VERSION 5.7 ;
  NOWIREEXTENSIONATPIN ON ;
  DIVIDERCHAR "/" ;
  BUSBITCHARS "[]" ;
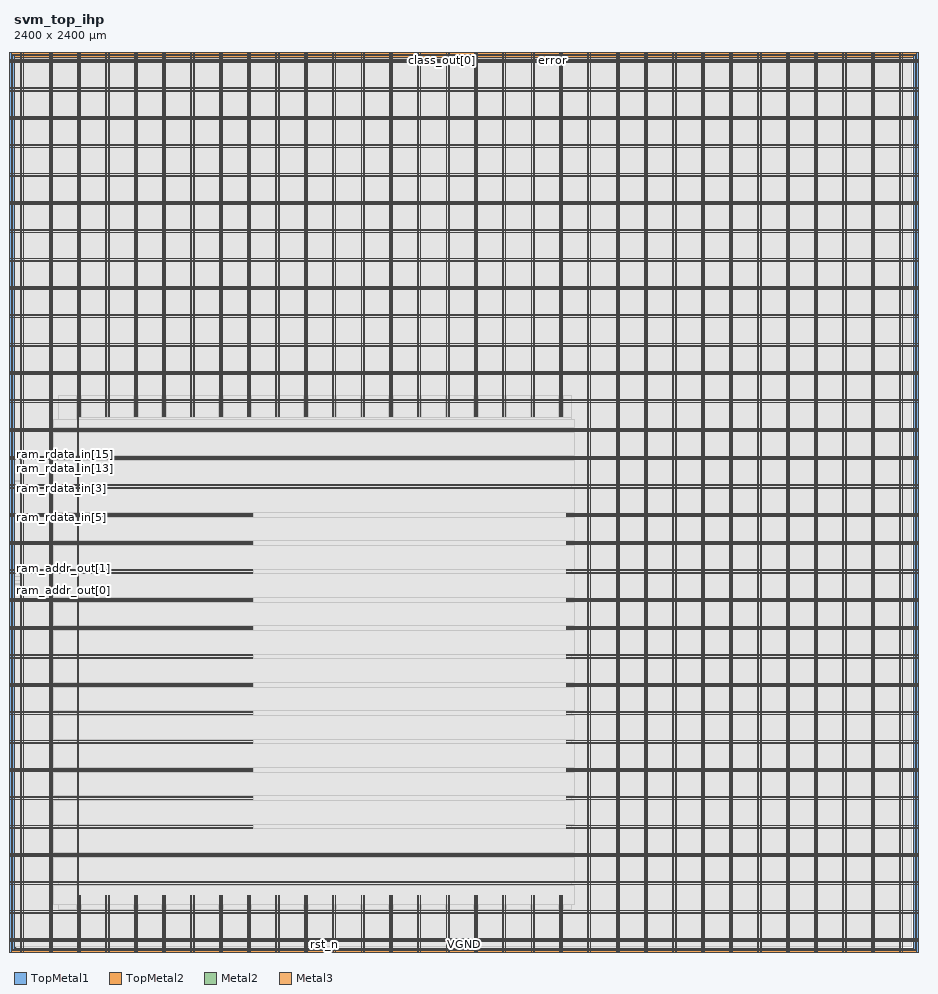
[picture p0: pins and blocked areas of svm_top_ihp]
MACRO svm_top_ihp
  CLASS BLOCK ;
  FOREIGN svm_top_ihp ;
  ORIGIN 0.000 0.000 ;
  SIZE 2400.000 BY 2400.000 ;
  PIN VGND
    DIRECTION INOUT ;
    USE GROUND ;
    PORT
      LAYER TopMetal1 ;
        RECT -10.740 -1.380 -5.740 2397.900 ;
    END
    PORT
      LAYER TopMetal1 ;
        RECT 2405.740 -1.380 2410.740 2397.900 ;
    END
    PORT
      LAYER TopMetal2 ;
        RECT -10.740 -1.380 2410.740 3.620 ;
    END
    PORT
      LAYER TopMetal2 ;
        RECT -10.740 2392.900 2410.740 2397.900 ;
    END
    PORT
      LAYER TopMetal1 ;
        RECT 24.460 -1.380 26.660 2397.900 ;
    END
    PORT
      LAYER TopMetal1 ;
        RECT 100.060 -1.380 102.260 2397.900 ;
    END
    PORT
      LAYER TopMetal1 ;
        RECT 175.660 -1.380 177.860 150.920 ;
    END
    PORT
      LAYER TopMetal1 ;
        RECT 175.660 1427.940 177.860 2397.900 ;
    END
    PORT
      LAYER TopMetal1 ;
        RECT 251.260 -1.380 253.460 150.920 ;
    END
    PORT
      LAYER TopMetal1 ;
        RECT 251.260 1427.940 253.460 2397.900 ;
    END
    PORT
      LAYER TopMetal1 ;
        RECT 326.860 -1.380 329.060 150.920 ;
    END
    PORT
      LAYER TopMetal1 ;
        RECT 326.860 1427.940 329.060 2397.900 ;
    END
    PORT
      LAYER TopMetal1 ;
        RECT 402.460 -1.380 404.660 150.920 ;
    END
    PORT
      LAYER TopMetal1 ;
        RECT 402.460 1427.940 404.660 2397.900 ;
    END
    PORT
      LAYER TopMetal1 ;
        RECT 478.060 -1.380 480.260 150.920 ;
    END
    PORT
      LAYER TopMetal1 ;
        RECT 478.060 1427.940 480.260 2397.900 ;
    END
    PORT
      LAYER TopMetal1 ;
        RECT 553.660 -1.380 555.860 150.920 ;
    END
    PORT
      LAYER TopMetal1 ;
        RECT 553.660 1427.940 555.860 2397.900 ;
    END
    PORT
      LAYER TopMetal1 ;
        RECT 629.260 -1.380 631.460 150.920 ;
    END
    PORT
      LAYER TopMetal1 ;
        RECT 629.260 1427.940 631.460 2397.900 ;
    END
    PORT
      LAYER TopMetal1 ;
        RECT 704.860 -1.380 707.060 150.920 ;
    END
    PORT
      LAYER TopMetal1 ;
        RECT 704.860 1427.940 707.060 2397.900 ;
    END
    PORT
      LAYER TopMetal1 ;
        RECT 780.460 -1.380 782.660 150.920 ;
    END
    PORT
      LAYER TopMetal1 ;
        RECT 780.460 1427.940 782.660 2397.900 ;
    END
    PORT
      LAYER TopMetal1 ;
        RECT 856.060 -1.380 858.260 150.920 ;
    END
    PORT
      LAYER TopMetal1 ;
        RECT 856.060 1427.940 858.260 2397.900 ;
    END
    PORT
      LAYER TopMetal1 ;
        RECT 931.660 -1.380 933.860 150.920 ;
    END
    PORT
      LAYER TopMetal1 ;
        RECT 931.660 1427.940 933.860 2397.900 ;
    END
    PORT
      LAYER TopMetal1 ;
        RECT 1007.260 -1.380 1009.460 150.920 ;
    END
    PORT
      LAYER TopMetal1 ;
        RECT 1007.260 1427.940 1009.460 2397.900 ;
    END
    PORT
      LAYER TopMetal1 ;
        RECT 1082.860 -1.380 1085.060 150.920 ;
    END
    PORT
      LAYER TopMetal1 ;
        RECT 1082.860 1427.940 1085.060 2397.900 ;
    END
    PORT
      LAYER TopMetal1 ;
        RECT 1158.460 -1.380 1160.660 150.920 ;
    END
    PORT
      LAYER TopMetal1 ;
        RECT 1158.460 1427.940 1160.660 2397.900 ;
    END
    PORT
      LAYER TopMetal1 ;
        RECT 1234.060 -1.380 1236.260 150.920 ;
    END
    PORT
      LAYER TopMetal1 ;
        RECT 1234.060 1427.940 1236.260 2397.900 ;
    END
    PORT
      LAYER TopMetal1 ;
        RECT 1309.660 -1.380 1311.860 150.920 ;
    END
    PORT
      LAYER TopMetal1 ;
        RECT 1309.660 1427.940 1311.860 2397.900 ;
    END
    PORT
      LAYER TopMetal1 ;
        RECT 1385.260 -1.380 1387.460 150.920 ;
    END
    PORT
      LAYER TopMetal1 ;
        RECT 1385.260 1427.940 1387.460 2397.900 ;
    END
    PORT
      LAYER TopMetal1 ;
        RECT 1460.860 -1.380 1463.060 150.920 ;
    END
    PORT
      LAYER TopMetal1 ;
        RECT 1460.860 1427.940 1463.060 2397.900 ;
    END
    PORT
      LAYER TopMetal1 ;
        RECT 1536.460 -1.380 1538.660 2397.900 ;
    END
    PORT
      LAYER TopMetal1 ;
        RECT 1612.060 -1.380 1614.260 2397.900 ;
    END
    PORT
      LAYER TopMetal1 ;
        RECT 1687.660 -1.380 1689.860 2397.900 ;
    END
    PORT
      LAYER TopMetal1 ;
        RECT 1763.260 -1.380 1765.460 2397.900 ;
    END
    PORT
      LAYER TopMetal1 ;
        RECT 1838.860 -1.380 1841.060 2397.900 ;
    END
    PORT
      LAYER TopMetal1 ;
        RECT 1914.460 -1.380 1916.660 2397.900 ;
    END
    PORT
      LAYER TopMetal1 ;
        RECT 1990.060 -1.380 1992.260 2397.900 ;
    END
    PORT
      LAYER TopMetal1 ;
        RECT 2065.660 -1.380 2067.860 2397.900 ;
    END
    PORT
      LAYER TopMetal1 ;
        RECT 2141.260 -1.380 2143.460 2397.900 ;
    END
    PORT
      LAYER TopMetal1 ;
        RECT 2216.860 -1.380 2219.060 2397.900 ;
    END
    PORT
      LAYER TopMetal1 ;
        RECT 2292.460 -1.380 2294.660 2397.900 ;
    END
    PORT
      LAYER TopMetal1 ;
        RECT 2368.060 -1.380 2370.260 2397.900 ;
    END
    PORT
      LAYER TopMetal2 ;
        RECT -10.740 33.820 2410.740 36.020 ;
    END
    PORT
      LAYER TopMetal2 ;
        RECT -10.740 109.420 2410.740 111.620 ;
    END
    PORT
      LAYER TopMetal2 ;
        RECT -10.740 185.020 2410.740 187.220 ;
    END
    PORT
      LAYER TopMetal2 ;
        RECT -10.740 260.620 2410.740 262.820 ;
    END
    PORT
      LAYER TopMetal2 ;
        RECT -10.740 336.220 637.000 338.420 ;
    END
    PORT
      LAYER TopMetal2 ;
        RECT -10.740 411.820 637.000 414.020 ;
    END
    PORT
      LAYER TopMetal2 ;
        RECT -10.740 487.420 637.000 489.620 ;
    END
    PORT
      LAYER TopMetal2 ;
        RECT -10.740 563.020 637.000 565.220 ;
    END
    PORT
      LAYER TopMetal2 ;
        RECT -10.740 638.620 637.000 640.820 ;
    END
    PORT
      LAYER TopMetal2 ;
        RECT -10.740 714.220 637.000 716.420 ;
    END
    PORT
      LAYER TopMetal2 ;
        RECT -10.740 789.820 637.000 792.020 ;
    END
    PORT
      LAYER TopMetal2 ;
        RECT -10.740 865.420 637.000 867.620 ;
    END
    PORT
      LAYER TopMetal2 ;
        RECT -10.740 941.020 637.000 943.220 ;
    END
    PORT
      LAYER TopMetal2 ;
        RECT -10.740 1016.620 637.000 1018.820 ;
    END
    PORT
      LAYER TopMetal2 ;
        RECT -10.740 1092.220 637.000 1094.420 ;
    END
    PORT
      LAYER TopMetal2 ;
        RECT -10.740 1167.820 637.000 1170.020 ;
    END
    PORT
      LAYER TopMetal2 ;
        RECT -10.740 1243.420 2410.740 1245.620 ;
    END
    PORT
      LAYER TopMetal2 ;
        RECT -10.740 1319.020 2410.740 1321.220 ;
    END
    PORT
      LAYER TopMetal2 ;
        RECT -10.740 1394.620 2410.740 1396.820 ;
    END
    PORT
      LAYER TopMetal2 ;
        RECT -10.740 1470.220 2410.740 1472.420 ;
    END
    PORT
      LAYER TopMetal2 ;
        RECT -10.740 1545.820 2410.740 1548.020 ;
    END
    PORT
      LAYER TopMetal2 ;
        RECT -10.740 1621.420 2410.740 1623.620 ;
    END
    PORT
      LAYER TopMetal2 ;
        RECT -10.740 1697.020 2410.740 1699.220 ;
    END
    PORT
      LAYER TopMetal2 ;
        RECT -10.740 1772.620 2410.740 1774.820 ;
    END
    PORT
      LAYER TopMetal2 ;
        RECT -10.740 1848.220 2410.740 1850.420 ;
    END
    PORT
      LAYER TopMetal2 ;
        RECT -10.740 1923.820 2410.740 1926.020 ;
    END
    PORT
      LAYER TopMetal2 ;
        RECT -10.740 1999.420 2410.740 2001.620 ;
    END
    PORT
      LAYER TopMetal2 ;
        RECT -10.740 2075.020 2410.740 2077.220 ;
    END
    PORT
      LAYER TopMetal2 ;
        RECT -10.740 2150.620 2410.740 2152.820 ;
    END
    PORT
      LAYER TopMetal2 ;
        RECT -10.740 2226.220 2410.740 2228.420 ;
    END
    PORT
      LAYER TopMetal2 ;
        RECT -10.740 2301.820 2410.740 2304.020 ;
    END
    PORT
      LAYER TopMetal2 ;
        RECT -10.740 2377.420 2410.740 2379.620 ;
    END
    PORT
      LAYER TopMetal2 ;
        RECT 1474.640 336.220 2410.740 338.420 ;
    END
    PORT
      LAYER TopMetal2 ;
        RECT 1474.640 411.820 2410.740 414.020 ;
    END
    PORT
      LAYER TopMetal2 ;
        RECT 1474.640 487.420 2410.740 489.620 ;
    END
    PORT
      LAYER TopMetal2 ;
        RECT 1474.640 563.020 2410.740 565.220 ;
    END
    PORT
      LAYER TopMetal2 ;
        RECT 1474.640 638.620 2410.740 640.820 ;
    END
    PORT
      LAYER TopMetal2 ;
        RECT 1474.640 714.220 2410.740 716.420 ;
    END
    PORT
      LAYER TopMetal2 ;
        RECT 1474.640 789.820 2410.740 792.020 ;
    END
    PORT
      LAYER TopMetal2 ;
        RECT 1474.640 865.420 2410.740 867.620 ;
    END
    PORT
      LAYER TopMetal2 ;
        RECT 1474.640 941.020 2410.740 943.220 ;
    END
    PORT
      LAYER TopMetal2 ;
        RECT 1474.640 1016.620 2410.740 1018.820 ;
    END
    PORT
      LAYER TopMetal2 ;
        RECT 1474.640 1092.220 2410.740 1094.420 ;
    END
    PORT
      LAYER TopMetal2 ;
        RECT 1474.640 1167.820 2410.740 1170.020 ;
    END
  END VGND
  PIN VPWR
    DIRECTION INOUT ;
    USE POWER ;
    PORT
      LAYER TopMetal1 ;
        RECT -3.740 5.620 1.260 2390.900 ;
    END
    PORT
      LAYER TopMetal1 ;
        RECT 2398.740 5.620 2403.740 2390.900 ;
    END
    PORT
      LAYER TopMetal2 ;
        RECT -3.740 5.620 2403.740 10.620 ;
    END
    PORT
      LAYER TopMetal2 ;
        RECT -3.740 2385.900 2403.740 2390.900 ;
    END
    PORT
      LAYER TopMetal1 ;
        RECT 18.260 -1.380 20.460 2397.900 ;
    END
    PORT
      LAYER TopMetal1 ;
        RECT 93.860 -1.380 96.060 2397.900 ;
    END
    PORT
      LAYER TopMetal1 ;
        RECT 169.460 -1.380 171.660 2397.900 ;
    END
    PORT
      LAYER TopMetal1 ;
        RECT 245.060 -1.380 247.260 150.920 ;
    END
    PORT
      LAYER TopMetal1 ;
        RECT 245.060 1427.940 247.260 2397.900 ;
    END
    PORT
      LAYER TopMetal1 ;
        RECT 320.660 -1.380 322.860 150.920 ;
    END
    PORT
      LAYER TopMetal1 ;
        RECT 320.660 1427.940 322.860 2397.900 ;
    END
    PORT
      LAYER TopMetal1 ;
        RECT 396.260 -1.380 398.460 150.920 ;
    END
    PORT
      LAYER TopMetal1 ;
        RECT 396.260 1427.940 398.460 2397.900 ;
    END
    PORT
      LAYER TopMetal1 ;
        RECT 471.860 -1.380 474.060 150.920 ;
    END
    PORT
      LAYER TopMetal1 ;
        RECT 471.860 1427.940 474.060 2397.900 ;
    END
    PORT
      LAYER TopMetal1 ;
        RECT 547.460 -1.380 549.660 150.920 ;
    END
    PORT
      LAYER TopMetal1 ;
        RECT 547.460 1427.940 549.660 2397.900 ;
    END
    PORT
      LAYER TopMetal1 ;
        RECT 623.060 -1.380 625.260 150.920 ;
    END
    PORT
      LAYER TopMetal1 ;
        RECT 623.060 1427.940 625.260 2397.900 ;
    END
    PORT
      LAYER TopMetal1 ;
        RECT 698.660 -1.380 700.860 150.920 ;
    END
    PORT
      LAYER TopMetal1 ;
        RECT 698.660 1427.940 700.860 2397.900 ;
    END
    PORT
      LAYER TopMetal1 ;
        RECT 774.260 -1.380 776.460 150.920 ;
    END
    PORT
      LAYER TopMetal1 ;
        RECT 774.260 1427.940 776.460 2397.900 ;
    END
    PORT
      LAYER TopMetal1 ;
        RECT 849.860 -1.380 852.060 150.920 ;
    END
    PORT
      LAYER TopMetal1 ;
        RECT 849.860 1427.940 852.060 2397.900 ;
    END
    PORT
      LAYER TopMetal1 ;
        RECT 925.460 -1.380 927.660 150.920 ;
    END
    PORT
      LAYER TopMetal1 ;
        RECT 925.460 1427.940 927.660 2397.900 ;
    END
    PORT
      LAYER TopMetal1 ;
        RECT 1001.060 -1.380 1003.260 150.920 ;
    END
    PORT
      LAYER TopMetal1 ;
        RECT 1001.060 1427.940 1003.260 2397.900 ;
    END
    PORT
      LAYER TopMetal1 ;
        RECT 1076.660 -1.380 1078.860 150.920 ;
    END
    PORT
      LAYER TopMetal1 ;
        RECT 1076.660 1427.940 1078.860 2397.900 ;
    END
    PORT
      LAYER TopMetal1 ;
        RECT 1152.260 -1.380 1154.460 150.920 ;
    END
    PORT
      LAYER TopMetal1 ;
        RECT 1152.260 1427.940 1154.460 2397.900 ;
    END
    PORT
      LAYER TopMetal1 ;
        RECT 1227.860 -1.380 1230.060 150.920 ;
    END
    PORT
      LAYER TopMetal1 ;
        RECT 1227.860 1427.940 1230.060 2397.900 ;
    END
    PORT
      LAYER TopMetal1 ;
        RECT 1303.460 -1.380 1305.660 150.920 ;
    END
    PORT
      LAYER TopMetal1 ;
        RECT 1303.460 1427.940 1305.660 2397.900 ;
    END
    PORT
      LAYER TopMetal1 ;
        RECT 1379.060 -1.380 1381.260 150.920 ;
    END
    PORT
      LAYER TopMetal1 ;
        RECT 1379.060 1427.940 1381.260 2397.900 ;
    END
    PORT
      LAYER TopMetal1 ;
        RECT 1454.660 -1.380 1456.860 150.920 ;
    END
    PORT
      LAYER TopMetal1 ;
        RECT 1454.660 1427.940 1456.860 2397.900 ;
    END
    PORT
      LAYER TopMetal1 ;
        RECT 1530.260 -1.380 1532.460 2397.900 ;
    END
    PORT
      LAYER TopMetal1 ;
        RECT 1605.860 -1.380 1608.060 2397.900 ;
    END
    PORT
      LAYER TopMetal1 ;
        RECT 1681.460 -1.380 1683.660 2397.900 ;
    END
    PORT
      LAYER TopMetal1 ;
        RECT 1757.060 -1.380 1759.260 2397.900 ;
    END
    PORT
      LAYER TopMetal1 ;
        RECT 1832.660 -1.380 1834.860 2397.900 ;
    END
    PORT
      LAYER TopMetal1 ;
        RECT 1908.260 -1.380 1910.460 2397.900 ;
    END
    PORT
      LAYER TopMetal1 ;
        RECT 1983.860 -1.380 1986.060 2397.900 ;
    END
    PORT
      LAYER TopMetal1 ;
        RECT 2059.460 -1.380 2061.660 2397.900 ;
    END
    PORT
      LAYER TopMetal1 ;
        RECT 2135.060 -1.380 2137.260 2397.900 ;
    END
    PORT
      LAYER TopMetal1 ;
        RECT 2210.660 -1.380 2212.860 2397.900 ;
    END
    PORT
      LAYER TopMetal1 ;
        RECT 2286.260 -1.380 2288.460 2397.900 ;
    END
    PORT
      LAYER TopMetal1 ;
        RECT 2361.860 -1.380 2364.060 2397.900 ;
    END
    PORT
      LAYER TopMetal2 ;
        RECT -10.740 27.620 2410.740 29.820 ;
    END
    PORT
      LAYER TopMetal2 ;
        RECT -10.740 103.220 2410.740 105.420 ;
    END
    PORT
      LAYER TopMetal2 ;
        RECT -10.740 178.820 2410.740 181.020 ;
    END
    PORT
      LAYER TopMetal2 ;
        RECT -10.740 254.420 2410.740 256.620 ;
    END
    PORT
      LAYER TopMetal2 ;
        RECT -10.740 330.020 637.000 332.220 ;
    END
    PORT
      LAYER TopMetal2 ;
        RECT -10.740 405.620 637.000 407.820 ;
    END
    PORT
      LAYER TopMetal2 ;
        RECT -10.740 481.220 637.000 483.420 ;
    END
    PORT
      LAYER TopMetal2 ;
        RECT -10.740 556.820 637.000 559.020 ;
    END
    PORT
      LAYER TopMetal2 ;
        RECT -10.740 632.420 637.000 634.620 ;
    END
    PORT
      LAYER TopMetal2 ;
        RECT -10.740 708.020 637.000 710.220 ;
    END
    PORT
      LAYER TopMetal2 ;
        RECT -10.740 783.620 637.000 785.820 ;
    END
    PORT
      LAYER TopMetal2 ;
        RECT -10.740 859.220 637.000 861.420 ;
    END
    PORT
      LAYER TopMetal2 ;
        RECT -10.740 934.820 637.000 937.020 ;
    END
    PORT
      LAYER TopMetal2 ;
        RECT -10.740 1010.420 637.000 1012.620 ;
    END
    PORT
      LAYER TopMetal2 ;
        RECT -10.740 1086.020 637.000 1088.220 ;
    END
    PORT
      LAYER TopMetal2 ;
        RECT -10.740 1161.620 637.000 1163.820 ;
    END
    PORT
      LAYER TopMetal2 ;
        RECT -10.740 1237.220 2410.740 1239.420 ;
    END
    PORT
      LAYER TopMetal2 ;
        RECT -10.740 1312.820 2410.740 1315.020 ;
    END
    PORT
      LAYER TopMetal2 ;
        RECT -10.740 1388.420 2410.740 1390.620 ;
    END
    PORT
      LAYER TopMetal2 ;
        RECT -10.740 1464.020 2410.740 1466.220 ;
    END
    PORT
      LAYER TopMetal2 ;
        RECT -10.740 1539.620 2410.740 1541.820 ;
    END
    PORT
      LAYER TopMetal2 ;
        RECT -10.740 1615.220 2410.740 1617.420 ;
    END
    PORT
      LAYER TopMetal2 ;
        RECT -10.740 1690.820 2410.740 1693.020 ;
    END
    PORT
      LAYER TopMetal2 ;
        RECT -10.740 1766.420 2410.740 1768.620 ;
    END
    PORT
      LAYER TopMetal2 ;
        RECT -10.740 1842.020 2410.740 1844.220 ;
    END
    PORT
      LAYER TopMetal2 ;
        RECT -10.740 1917.620 2410.740 1919.820 ;
    END
    PORT
      LAYER TopMetal2 ;
        RECT -10.740 1993.220 2410.740 1995.420 ;
    END
    PORT
      LAYER TopMetal2 ;
        RECT -10.740 2068.820 2410.740 2071.020 ;
    END
    PORT
      LAYER TopMetal2 ;
        RECT -10.740 2144.420 2410.740 2146.620 ;
    END
    PORT
      LAYER TopMetal2 ;
        RECT -10.740 2220.020 2410.740 2222.220 ;
    END
    PORT
      LAYER TopMetal2 ;
        RECT -10.740 2295.620 2410.740 2297.820 ;
    END
    PORT
      LAYER TopMetal2 ;
        RECT -10.740 2371.220 2410.740 2373.420 ;
    END
    PORT
      LAYER TopMetal2 ;
        RECT 1474.640 330.020 2410.740 332.220 ;
    END
    PORT
      LAYER TopMetal2 ;
        RECT 1474.640 405.620 2410.740 407.820 ;
    END
    PORT
      LAYER TopMetal2 ;
        RECT 1474.640 481.220 2410.740 483.420 ;
    END
    PORT
      LAYER TopMetal2 ;
        RECT 1474.640 556.820 2410.740 559.020 ;
    END
    PORT
      LAYER TopMetal2 ;
        RECT 1474.640 632.420 2410.740 634.620 ;
    END
    PORT
      LAYER TopMetal2 ;
        RECT 1474.640 708.020 2410.740 710.220 ;
    END
    PORT
      LAYER TopMetal2 ;
        RECT 1474.640 783.620 2410.740 785.820 ;
    END
    PORT
      LAYER TopMetal2 ;
        RECT 1474.640 859.220 2410.740 861.420 ;
    END
    PORT
      LAYER TopMetal2 ;
        RECT 1474.640 934.820 2410.740 937.020 ;
    END
    PORT
      LAYER TopMetal2 ;
        RECT 1474.640 1010.420 2410.740 1012.620 ;
    END
    PORT
      LAYER TopMetal2 ;
        RECT 1474.640 1086.020 2410.740 1088.220 ;
    END
    PORT
      LAYER TopMetal2 ;
        RECT 1474.640 1161.620 2410.740 1163.820 ;
    END
  END VPWR
  PIN class_out[0]
    DIRECTION OUTPUT ;
    USE SIGNAL ;
    ANTENNADIFFAREA 0.708600 ;
    PORT
      LAYER Metal2 ;
        RECT 1141.720 2399.600 1142.120 2400.000 ;
    END
  END class_out[0]
  PIN class_out[1]
    DIRECTION OUTPUT ;
    USE SIGNAL ;
    ANTENNADIFFAREA 0.708600 ;
    PORT
      LAYER Metal2 ;
        RECT 1140.760 2399.600 1141.160 2400.000 ;
    END
  END class_out[1]
  PIN class_out[2]
    DIRECTION OUTPUT ;
    USE SIGNAL ;
    ANTENNADIFFAREA 0.708600 ;
    PORT
      LAYER Metal2 ;
        RECT 1139.800 2399.600 1140.200 2400.000 ;
    END
  END class_out[2]
  PIN clk
    DIRECTION INPUT ;
    USE SIGNAL ;
    ANTENNAGATEAREA 2.901600 ;
    PORT
      LAYER Metal2 ;
        RECT 1374.040 2399.600 1374.440 2400.000 ;
    END
  END clk
  PIN done
    DIRECTION OUTPUT ;
    USE SIGNAL ;
    ANTENNADIFFAREA 0.708600 ;
    PORT
      LAYER Metal2 ;
        RECT 1183.000 2399.600 1183.400 2400.000 ;
    END
  END done
  PIN error
    DIRECTION OUTPUT ;
    USE SIGNAL ;
    ANTENNADIFFAREA 0.708600 ;
    PORT
      LAYER Metal2 ;
        RECT 1437.400 2399.600 1437.800 2400.000 ;
    END
  END error
  PIN error_code[0]
    DIRECTION OUTPUT ;
    USE SIGNAL ;
    ANTENNADIFFAREA 0.708600 ;
    PORT
      LAYER Metal2 ;
        RECT 1436.440 2399.600 1436.840 2400.000 ;
    END
  END error_code[0]
  PIN error_code[1]
    DIRECTION OUTPUT ;
    USE SIGNAL ;
    ANTENNADIFFAREA 0.708600 ;
    PORT
      LAYER Metal2 ;
        RECT 1223.320 2399.600 1223.720 2400.000 ;
    END
  END error_code[1]
  PIN error_code[2]
    DIRECTION OUTPUT ;
    USE SIGNAL ;
    ANTENNADIFFAREA 0.708600 ;
    PORT
      LAYER Metal2 ;
        RECT 1435.480 2399.600 1435.880 2400.000 ;
    END
  END error_code[2]
  PIN error_code[3]
    DIRECTION OUTPUT ;
    USE SIGNAL ;
    ANTENNADIFFAREA 0.708600 ;
    PORT
      LAYER Metal2 ;
        RECT 1434.520 2399.600 1434.920 2400.000 ;
    END
  END error_code[3]
  PIN irq_done
    DIRECTION OUTPUT ;
    USE SIGNAL ;
    ANTENNADIFFAREA 0.708600 ;
    PORT
      LAYER Metal2 ;
        RECT 1134.040 2399.600 1134.440 2400.000 ;
    END
  END irq_done
  PIN irq_sample_rdy
    DIRECTION OUTPUT ;
    USE SIGNAL ;
    ANTENNADIFFAREA 0.708600 ;
    PORT
      LAYER Metal2 ;
        RECT 1053.400 2399.600 1053.800 2400.000 ;
    END
  END irq_sample_rdy
  PIN ram_addr_out[0]
    DIRECTION OUTPUT ;
    USE SIGNAL ;
    ANTENNADIFFAREA 0.708600 ;
    PORT
      LAYER Metal3 ;
        RECT 0.000 963.700 0.400 964.100 ;
    END
  END ram_addr_out[0]
  PIN ram_addr_out[10]
    DIRECTION OUTPUT ;
    USE SIGNAL ;
    ANTENNADIFFAREA 0.708600 ;
    PORT
      LAYER Metal2 ;
        RECT 1003.480 2399.600 1003.880 2400.000 ;
    END
  END ram_addr_out[10]
  PIN ram_addr_out[11]
    DIRECTION OUTPUT ;
    USE SIGNAL ;
    ANTENNADIFFAREA 0.708600 ;
    PORT
      LAYER Metal2 ;
        RECT 1017.880 2399.600 1018.280 2400.000 ;
    END
  END ram_addr_out[11]
  PIN ram_addr_out[12]
    DIRECTION OUTPUT ;
    USE SIGNAL ;
    ANTENNADIFFAREA 0.708600 ;
    PORT
      LAYER Metal2 ;
        RECT 1027.480 2399.600 1027.880 2400.000 ;
    END
  END ram_addr_out[12]
  PIN ram_addr_out[13]
    DIRECTION OUTPUT ;
    USE SIGNAL ;
    ANTENNADIFFAREA 0.708600 ;
    PORT
      LAYER Metal2 ;
        RECT 1031.320 2399.600 1031.720 2400.000 ;
    END
  END ram_addr_out[13]
  PIN ram_addr_out[14]
    DIRECTION OUTPUT ;
    USE SIGNAL ;
    ANTENNADIFFAREA 0.708600 ;
    PORT
      LAYER Metal2 ;
        RECT 1039.960 2399.600 1040.360 2400.000 ;
    END
  END ram_addr_out[14]
  PIN ram_addr_out[15]
    DIRECTION OUTPUT ;
    USE SIGNAL ;
    ANTENNADIFFAREA 0.708600 ;
    PORT
      LAYER Metal2 ;
        RECT 1052.440 2399.600 1052.840 2400.000 ;
    END
  END ram_addr_out[15]
  PIN ram_addr_out[16]
    DIRECTION OUTPUT ;
    USE SIGNAL ;
    ANTENNADIFFAREA 0.708600 ;
    PORT
      LAYER Metal2 ;
        RECT 1019.800 2399.600 1020.200 2400.000 ;
    END
  END ram_addr_out[16]
  PIN ram_addr_out[17]
    DIRECTION OUTPUT ;
    USE SIGNAL ;
    ANTENNADIFFAREA 0.708600 ;
    PORT
      LAYER Metal2 ;
        RECT 1043.800 2399.600 1044.200 2400.000 ;
    END
  END ram_addr_out[17]
  PIN ram_addr_out[18]
    DIRECTION OUTPUT ;
    USE SIGNAL ;
    ANTENNADIFFAREA 0.708600 ;
    PORT
      LAYER Metal2 ;
        RECT 1046.680 2399.600 1047.080 2400.000 ;
    END
  END ram_addr_out[18]
  PIN ram_addr_out[1]
    DIRECTION OUTPUT ;
    USE SIGNAL ;
    ANTENNADIFFAREA 0.708600 ;
    PORT
      LAYER Metal3 ;
        RECT 0.000 1000.660 0.400 1001.060 ;
    END
  END ram_addr_out[1]
  PIN ram_addr_out[2]
    DIRECTION OUTPUT ;
    USE SIGNAL ;
    ANTENNADIFFAREA 0.708600 ;
    PORT
      LAYER Metal3 ;
        RECT 0.000 983.020 0.400 983.420 ;
    END
  END ram_addr_out[2]
  PIN ram_addr_out[3]
    DIRECTION OUTPUT ;
    USE SIGNAL ;
    ANTENNADIFFAREA 0.708600 ;
    PORT
      LAYER Metal3 ;
        RECT 0.000 981.340 0.400 981.740 ;
    END
  END ram_addr_out[3]
  PIN ram_addr_out[4]
    DIRECTION OUTPUT ;
    USE SIGNAL ;
    ANTENNADIFFAREA 0.708600 ;
    PORT
      LAYER Metal3 ;
        RECT 0.000 958.660 0.400 959.060 ;
    END
  END ram_addr_out[4]
  PIN ram_addr_out[5]
    DIRECTION OUTPUT ;
    USE SIGNAL ;
    ANTENNADIFFAREA 0.708600 ;
    PORT
      LAYER Metal3 ;
        RECT 0.000 957.820 0.400 958.220 ;
    END
  END ram_addr_out[5]
  PIN ram_addr_out[6]
    DIRECTION OUTPUT ;
    USE SIGNAL ;
    ANTENNADIFFAREA 0.708600 ;
    PORT
      LAYER Metal3 ;
        RECT 0.000 959.500 0.400 959.900 ;
    END
  END ram_addr_out[6]
  PIN ram_addr_out[7]
    DIRECTION OUTPUT ;
    USE SIGNAL ;
    ANTENNADIFFAREA 0.708600 ;
    PORT
      LAYER Metal3 ;
        RECT 0.000 968.740 0.400 969.140 ;
    END
  END ram_addr_out[7]
  PIN ram_addr_out[8]
    DIRECTION OUTPUT ;
    USE SIGNAL ;
    ANTENNADIFFAREA 0.708600 ;
    PORT
      LAYER Metal2 ;
        RECT 1020.760 2399.600 1021.160 2400.000 ;
    END
  END ram_addr_out[8]
  PIN ram_addr_out[9]
    DIRECTION OUTPUT ;
    USE SIGNAL ;
    ANTENNADIFFAREA 0.708600 ;
    PORT
      LAYER Metal2 ;
        RECT 1010.200 2399.600 1010.600 2400.000 ;
    END
  END ram_addr_out[9]
  PIN ram_rdata_in[0]
    DIRECTION INPUT ;
    USE SIGNAL ;
    ANTENNAGATEAREA 0.180700 ;
    PORT
      LAYER Metal3 ;
        RECT 0.000 1329.100 0.400 1329.500 ;
    END
  END ram_rdata_in[0]
  PIN ram_rdata_in[10]
    DIRECTION INPUT ;
    USE SIGNAL ;
    ANTENNAGATEAREA 0.180700 ;
    PORT
      LAYER Metal3 ;
        RECT 0.000 1161.100 0.400 1161.500 ;
    END
  END ram_rdata_in[10]
  PIN ram_rdata_in[11]
    DIRECTION INPUT ;
    USE SIGNAL ;
    ANTENNAGATEAREA 0.180700 ;
    PORT
      LAYER Metal3 ;
        RECT 0.000 1328.260 0.400 1328.660 ;
    END
  END ram_rdata_in[11]
  PIN ram_rdata_in[12]
    DIRECTION INPUT ;
    USE SIGNAL ;
    ANTENNAGATEAREA 0.180700 ;
    PORT
      LAYER Metal3 ;
        RECT 0.000 1295.500 0.400 1295.900 ;
    END
  END ram_rdata_in[12]
  PIN ram_rdata_in[13]
    DIRECTION INPUT ;
    USE SIGNAL ;
    ANTENNAGATEAREA 0.180700 ;
    PORT
      LAYER Metal3 ;
        RECT 0.000 1287.940 0.400 1288.340 ;
    END
  END ram_rdata_in[13]
  PIN ram_rdata_in[14]
    DIRECTION INPUT ;
    USE SIGNAL ;
    ANTENNAGATEAREA 0.180700 ;
    PORT
      LAYER Metal3 ;
        RECT 0.000 1294.660 0.400 1295.060 ;
    END
  END ram_rdata_in[14]
  PIN ram_rdata_in[15]
    DIRECTION INPUT ;
    USE SIGNAL ;
    ANTENNAGATEAREA 0.180700 ;
    PORT
      LAYER Metal3 ;
        RECT 0.000 1327.420 0.400 1327.820 ;
    END
  END ram_rdata_in[15]
  PIN ram_rdata_in[1]
    DIRECTION INPUT ;
    USE SIGNAL ;
    ANTENNAGATEAREA 0.180700 ;
    PORT
      LAYER Metal3 ;
        RECT 0.000 1320.700 0.400 1321.100 ;
    END
  END ram_rdata_in[1]
  PIN ram_rdata_in[2]
    DIRECTION INPUT ;
    USE SIGNAL ;
    ANTENNAGATEAREA 0.180700 ;
    PORT
      LAYER Metal3 ;
        RECT 0.000 1326.580 0.400 1326.980 ;
    END
  END ram_rdata_in[2]
  PIN ram_rdata_in[3]
    DIRECTION INPUT ;
    USE SIGNAL ;
    ANTENNAGATEAREA 0.180700 ;
    PORT
      LAYER Metal3 ;
        RECT 0.000 1257.700 0.400 1258.100 ;
    END
  END ram_rdata_in[3]
  PIN ram_rdata_in[4]
    DIRECTION INPUT ;
    USE SIGNAL ;
    ANTENNAGATEAREA 0.180700 ;
    PORT
      LAYER Metal3 ;
        RECT 0.000 1160.260 0.400 1160.660 ;
    END
  END ram_rdata_in[4]
  PIN ram_rdata_in[5]
    DIRECTION INPUT ;
    USE SIGNAL ;
    ANTENNAGATEAREA 0.180700 ;
    PORT
      LAYER Metal3 ;
        RECT 0.000 1159.420 0.400 1159.820 ;
    END
  END ram_rdata_in[5]
  PIN ram_rdata_in[6]
    DIRECTION INPUT ;
    USE SIGNAL ;
    ANTENNAGATEAREA 0.180700 ;
    PORT
      LAYER Metal3 ;
        RECT 0.000 1325.740 0.400 1326.140 ;
    END
  END ram_rdata_in[6]
  PIN ram_rdata_in[7]
    DIRECTION INPUT ;
    USE SIGNAL ;
    ANTENNAGATEAREA 0.180700 ;
    PORT
      LAYER Metal3 ;
        RECT 0.000 1254.340 0.400 1254.740 ;
    END
  END ram_rdata_in[7]
  PIN ram_rdata_in[8]
    DIRECTION INPUT ;
    USE SIGNAL ;
    ANTENNAGATEAREA 0.180700 ;
    PORT
      LAYER Metal3 ;
        RECT 0.000 1324.900 0.400 1325.300 ;
    END
  END ram_rdata_in[8]
  PIN ram_rdata_in[9]
    DIRECTION INPUT ;
    USE SIGNAL ;
    ANTENNAGATEAREA 0.180700 ;
    PORT
      LAYER Metal3 ;
        RECT 0.000 1299.700 0.400 1300.100 ;
    END
  END ram_rdata_in[9]
  PIN ram_ren_out
    DIRECTION OUTPUT ;
    USE SIGNAL ;
    ANTENNADIFFAREA 0.708600 ;
    PORT
      LAYER Metal3 ;
        RECT 0.000 990.580 0.400 990.980 ;
    END
  END ram_ren_out
  PIN rst_n
    DIRECTION INPUT ;
    USE SIGNAL ;
    ANTENNAGATEAREA 0.180700 ;
    PORT
      LAYER Metal2 ;
        RECT 827.800 0.000 828.200 0.400 ;
    END
  END rst_n
  PIN sample_rdy
    DIRECTION OUTPUT ;
    USE SIGNAL ;
    ANTENNADIFFAREA 0.708600 ;
    PORT
      LAYER Metal2 ;
        RECT 1051.480 2399.600 1051.880 2400.000 ;
    END
  END sample_rdy
  PIN spi_csn
    DIRECTION INPUT ;
    USE SIGNAL ;
    ANTENNAGATEAREA 0.180700 ;
    PORT
      LAYER Metal2 ;
        RECT 1164.760 2399.600 1165.160 2400.000 ;
    END
  END spi_csn
  PIN spi_miso
    DIRECTION OUTPUT ;
    USE SIGNAL ;
    ANTENNADIFFAREA 0.708600 ;
    PORT
      LAYER Metal2 ;
        RECT 1072.600 2399.600 1073.000 2400.000 ;
    END
  END spi_miso
  PIN spi_mosi
    DIRECTION INPUT ;
    USE SIGNAL ;
    ANTENNAGATEAREA 0.180700 ;
    PORT
      LAYER Metal2 ;
        RECT 1212.760 2399.600 1213.160 2400.000 ;
    END
  END spi_mosi
  PIN spi_sclk
    DIRECTION INPUT ;
    USE SIGNAL ;
    ANTENNAGATEAREA 0.180700 ;
    PORT
      LAYER Metal2 ;
        RECT 1158.040 2399.600 1158.440 2400.000 ;
    END
  END spi_sclk
  OBS
      LAYER GatPoly ;
        RECT 5.760 14.970 2394.240 2381.550 ;
      LAYER Metal1 ;
        RECT 5.760 14.900 2394.240 2381.620 ;
      LAYER Metal2 ;
        RECT 6.135 2399.390 1003.270 2399.980 ;
        RECT 1004.090 2399.390 1009.990 2399.980 ;
        RECT 1010.810 2399.390 1017.670 2399.980 ;
        RECT 1018.490 2399.390 1019.590 2399.980 ;
        RECT 1020.410 2399.390 1020.550 2399.980 ;
        RECT 1021.370 2399.390 1027.270 2399.980 ;
        RECT 1028.090 2399.390 1031.110 2399.980 ;
        RECT 1031.930 2399.390 1039.750 2399.980 ;
        RECT 1040.570 2399.390 1043.590 2399.980 ;
        RECT 1044.410 2399.390 1046.470 2399.980 ;
        RECT 1047.290 2399.390 1051.270 2399.980 ;
        RECT 1052.090 2399.390 1052.230 2399.980 ;
        RECT 1053.050 2399.390 1053.190 2399.980 ;
        RECT 1054.010 2399.390 1072.390 2399.980 ;
        RECT 1073.210 2399.390 1133.830 2399.980 ;
        RECT 1134.650 2399.390 1139.590 2399.980 ;
        RECT 1140.410 2399.390 1140.550 2399.980 ;
        RECT 1141.370 2399.390 1141.510 2399.980 ;
        RECT 1142.330 2399.390 1157.830 2399.980 ;
        RECT 1158.650 2399.390 1164.550 2399.980 ;
        RECT 1165.370 2399.390 1182.790 2399.980 ;
        RECT 1183.610 2399.390 1212.550 2399.980 ;
        RECT 1213.370 2399.390 1223.110 2399.980 ;
        RECT 1223.930 2399.390 1373.830 2399.980 ;
        RECT 1374.650 2399.390 1434.310 2399.980 ;
        RECT 1435.130 2399.390 1435.270 2399.980 ;
        RECT 1436.090 2399.390 1436.230 2399.980 ;
        RECT 1437.050 2399.390 1437.190 2399.980 ;
        RECT 1438.010 2399.390 2370.080 2399.980 ;
        RECT 6.135 0.610 2370.080 2399.390 ;
        RECT 6.135 0.400 827.590 0.610 ;
        RECT 828.410 0.400 2370.080 0.610 ;
      LAYER Metal3 ;
        RECT 0.400 1329.710 2370.125 2381.500 ;
        RECT 0.610 1328.890 2370.125 1329.710 ;
        RECT 0.400 1328.870 2370.125 1328.890 ;
        RECT 0.610 1328.050 2370.125 1328.870 ;
        RECT 0.400 1328.030 2370.125 1328.050 ;
        RECT 0.610 1327.210 2370.125 1328.030 ;
        RECT 0.400 1327.190 2370.125 1327.210 ;
        RECT 0.610 1326.370 2370.125 1327.190 ;
        RECT 0.400 1326.350 2370.125 1326.370 ;
        RECT 0.610 1325.530 2370.125 1326.350 ;
        RECT 0.400 1325.510 2370.125 1325.530 ;
        RECT 0.610 1324.690 2370.125 1325.510 ;
        RECT 0.400 1321.310 2370.125 1324.690 ;
        RECT 0.610 1320.490 2370.125 1321.310 ;
        RECT 0.400 1300.310 2370.125 1320.490 ;
        RECT 0.610 1299.490 2370.125 1300.310 ;
        RECT 0.400 1296.110 2370.125 1299.490 ;
        RECT 0.610 1295.290 2370.125 1296.110 ;
        RECT 0.400 1295.270 2370.125 1295.290 ;
        RECT 0.610 1294.450 2370.125 1295.270 ;
        RECT 0.400 1288.550 2370.125 1294.450 ;
        RECT 0.610 1287.730 2370.125 1288.550 ;
        RECT 0.400 1258.310 2370.125 1287.730 ;
        RECT 0.610 1257.490 2370.125 1258.310 ;
        RECT 0.400 1254.950 2370.125 1257.490 ;
        RECT 0.610 1254.130 2370.125 1254.950 ;
        RECT 0.400 1161.710 2370.125 1254.130 ;
        RECT 0.610 1160.890 2370.125 1161.710 ;
        RECT 0.400 1160.870 2370.125 1160.890 ;
        RECT 0.610 1160.050 2370.125 1160.870 ;
        RECT 0.400 1160.030 2370.125 1160.050 ;
        RECT 0.610 1159.210 2370.125 1160.030 ;
        RECT 0.400 1001.270 2370.125 1159.210 ;
        RECT 0.610 1000.450 2370.125 1001.270 ;
        RECT 0.400 991.190 2370.125 1000.450 ;
        RECT 0.610 990.370 2370.125 991.190 ;
        RECT 0.400 983.630 2370.125 990.370 ;
        RECT 0.610 982.810 2370.125 983.630 ;
        RECT 0.400 981.950 2370.125 982.810 ;
        RECT 0.610 981.130 2370.125 981.950 ;
        RECT 0.400 969.350 2370.125 981.130 ;
        RECT 0.610 968.530 2370.125 969.350 ;
        RECT 0.400 964.310 2370.125 968.530 ;
        RECT 0.610 963.490 2370.125 964.310 ;
        RECT 0.400 960.110 2370.125 963.490 ;
        RECT 0.610 959.290 2370.125 960.110 ;
        RECT 0.400 959.270 2370.125 959.290 ;
        RECT 0.610 958.450 2370.125 959.270 ;
        RECT 0.400 958.430 2370.125 958.450 ;
        RECT 0.610 957.610 2370.125 958.430 ;
        RECT 0.400 15.020 2370.125 957.610 ;
      LAYER Metal4 ;
        RECT 18.440 14.975 2370.080 2381.545 ;
      LAYER Metal5 ;
        RECT 18.395 14.810 2370.125 2381.710 ;
      LAYER TopMetal1 ;
        RECT 118.260 114.490 167.820 1484.110 ;
        RECT 173.300 1426.300 174.020 1484.110 ;
        RECT 179.500 1426.300 243.420 1484.110 ;
        RECT 248.900 1426.300 249.620 1484.110 ;
        RECT 255.100 1426.300 319.020 1484.110 ;
        RECT 324.500 1426.300 325.220 1484.110 ;
        RECT 330.700 1426.300 394.620 1484.110 ;
        RECT 400.100 1426.300 400.820 1484.110 ;
        RECT 406.300 1426.300 470.220 1484.110 ;
        RECT 475.700 1426.300 476.420 1484.110 ;
        RECT 481.900 1426.300 545.820 1484.110 ;
        RECT 551.300 1426.300 552.020 1484.110 ;
        RECT 557.500 1426.300 621.420 1484.110 ;
        RECT 626.900 1426.300 627.620 1484.110 ;
        RECT 633.100 1426.300 697.020 1484.110 ;
        RECT 702.500 1426.300 703.220 1484.110 ;
        RECT 708.700 1426.300 772.620 1484.110 ;
        RECT 778.100 1426.300 778.820 1484.110 ;
        RECT 784.300 1426.300 848.220 1484.110 ;
        RECT 853.700 1426.300 854.420 1484.110 ;
        RECT 859.900 1426.300 923.820 1484.110 ;
        RECT 929.300 1426.300 930.020 1484.110 ;
        RECT 935.500 1426.300 999.420 1484.110 ;
        RECT 1004.900 1426.300 1005.620 1484.110 ;
        RECT 1011.100 1426.300 1075.020 1484.110 ;
        RECT 1080.500 1426.300 1081.220 1484.110 ;
        RECT 1086.700 1426.300 1150.620 1484.110 ;
        RECT 1156.100 1426.300 1156.820 1484.110 ;
        RECT 1162.300 1426.300 1226.220 1484.110 ;
        RECT 1231.700 1426.300 1232.420 1484.110 ;
        RECT 1237.900 1426.300 1301.820 1484.110 ;
        RECT 1307.300 1426.300 1308.020 1484.110 ;
        RECT 1313.500 1426.300 1377.420 1484.110 ;
        RECT 1382.900 1426.300 1383.620 1484.110 ;
        RECT 1389.100 1426.300 1453.020 1484.110 ;
        RECT 1458.500 1426.300 1459.220 1484.110 ;
        RECT 1464.700 1426.300 1487.460 1484.110 ;
        RECT 173.300 152.560 1487.460 1426.300 ;
        RECT 173.300 114.490 174.020 152.560 ;
        RECT 179.500 114.490 243.420 152.560 ;
        RECT 248.900 114.490 249.620 152.560 ;
        RECT 255.100 114.490 319.020 152.560 ;
        RECT 324.500 114.490 325.220 152.560 ;
        RECT 330.700 114.490 394.620 152.560 ;
        RECT 400.100 114.490 400.820 152.560 ;
        RECT 406.300 114.490 470.220 152.560 ;
        RECT 475.700 114.490 476.420 152.560 ;
        RECT 481.900 114.490 545.820 152.560 ;
        RECT 551.300 114.490 552.020 152.560 ;
        RECT 557.500 114.490 621.420 152.560 ;
        RECT 626.900 114.490 627.620 152.560 ;
        RECT 633.100 114.490 697.020 152.560 ;
        RECT 702.500 114.490 703.220 152.560 ;
        RECT 708.700 114.490 772.620 152.560 ;
        RECT 778.100 114.490 778.820 152.560 ;
        RECT 784.300 114.490 848.220 152.560 ;
        RECT 853.700 114.490 854.420 152.560 ;
        RECT 859.900 114.490 923.820 152.560 ;
        RECT 929.300 114.490 930.020 152.560 ;
        RECT 935.500 114.490 999.420 152.560 ;
        RECT 1004.900 114.490 1005.620 152.560 ;
        RECT 1011.100 114.490 1075.020 152.560 ;
        RECT 1080.500 114.490 1081.220 152.560 ;
        RECT 1086.700 114.490 1150.620 152.560 ;
        RECT 1156.100 114.490 1156.820 152.560 ;
        RECT 1162.300 114.490 1226.220 152.560 ;
        RECT 1231.700 114.490 1232.420 152.560 ;
        RECT 1237.900 114.490 1301.820 152.560 ;
        RECT 1307.300 114.490 1308.020 152.560 ;
        RECT 1313.500 114.490 1377.420 152.560 ;
        RECT 1382.900 114.490 1383.620 152.560 ;
        RECT 1389.100 114.490 1453.020 152.560 ;
        RECT 1458.500 114.490 1459.220 152.560 ;
        RECT 1464.700 114.490 1487.460 152.560 ;
      LAYER TopMetal2 ;
        RECT 105.760 1398.820 1493.920 1421.220 ;
        RECT 105.760 1323.220 1493.920 1386.420 ;
        RECT 105.760 1247.620 1493.920 1310.820 ;
        RECT 105.760 1172.020 1493.920 1235.220 ;
        RECT 639.000 1159.620 1472.640 1172.020 ;
        RECT 105.760 1096.420 1493.920 1159.620 ;
        RECT 639.000 1084.020 1472.640 1096.420 ;
        RECT 105.760 1020.820 1493.920 1084.020 ;
        RECT 639.000 1008.420 1472.640 1020.820 ;
        RECT 105.760 945.220 1493.920 1008.420 ;
        RECT 639.000 932.820 1472.640 945.220 ;
        RECT 105.760 869.620 1493.920 932.820 ;
        RECT 639.000 857.220 1472.640 869.620 ;
        RECT 105.760 794.020 1493.920 857.220 ;
        RECT 639.000 781.620 1472.640 794.020 ;
        RECT 105.760 718.420 1493.920 781.620 ;
        RECT 639.000 706.020 1472.640 718.420 ;
        RECT 105.760 642.820 1493.920 706.020 ;
        RECT 639.000 630.420 1472.640 642.820 ;
        RECT 105.760 567.220 1493.920 630.420 ;
        RECT 639.000 554.820 1472.640 567.220 ;
        RECT 105.760 491.620 1493.920 554.820 ;
        RECT 639.000 479.220 1472.640 491.620 ;
        RECT 105.760 416.020 1493.920 479.220 ;
        RECT 639.000 403.620 1472.640 416.020 ;
        RECT 105.760 340.420 1493.920 403.620 ;
        RECT 639.000 328.020 1472.640 340.420 ;
        RECT 105.760 264.820 1493.920 328.020 ;
        RECT 105.760 189.220 1493.920 252.420 ;
        RECT 105.760 127.620 1493.920 176.820 ;
  END
END svm_top_ihp
END LIBRARY

